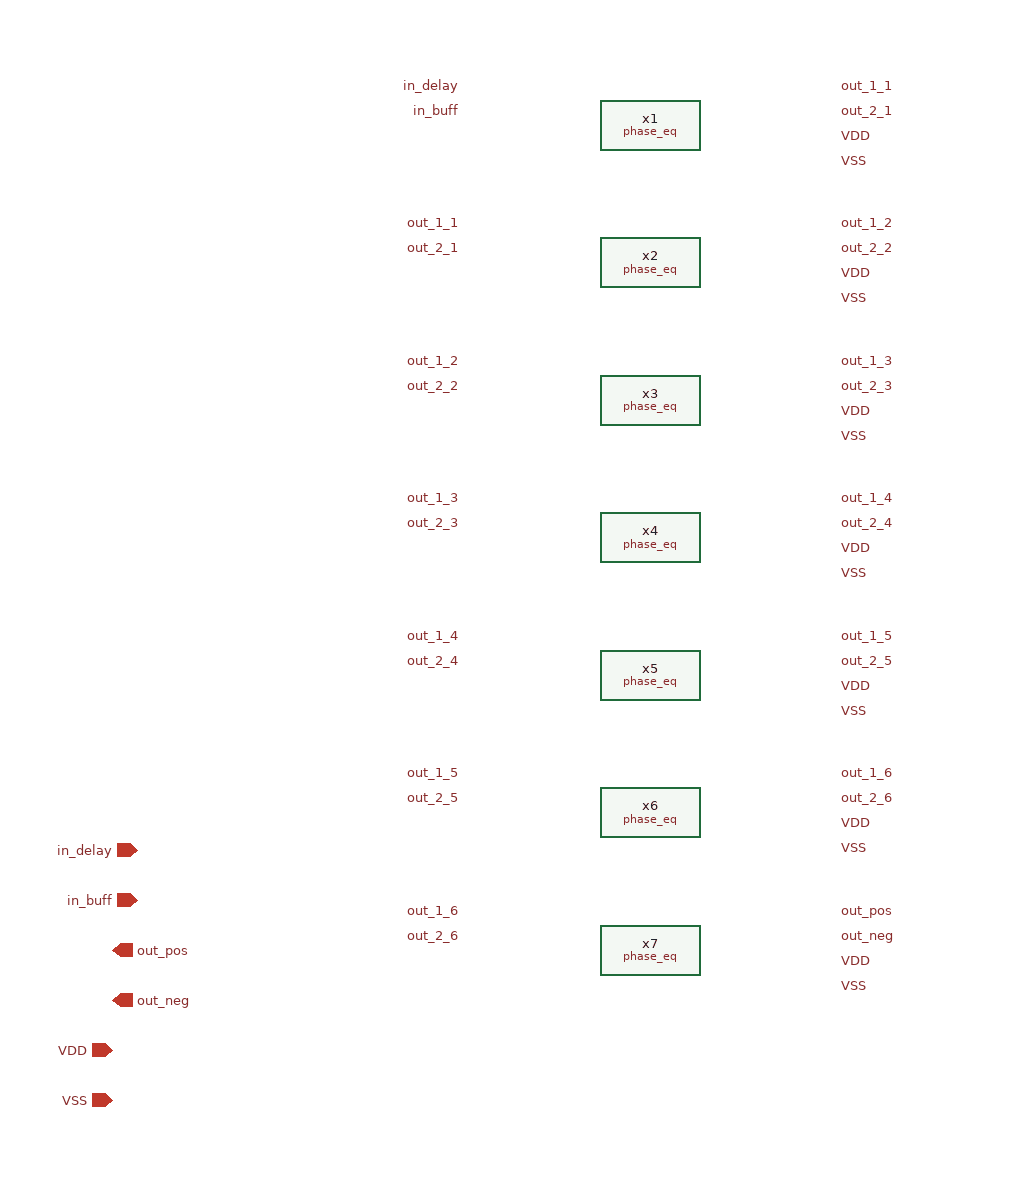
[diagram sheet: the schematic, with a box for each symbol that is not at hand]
v {xschem version=3.4.5 file_version=1.2
}
G {}
K {}
V {}
S {}
E {}
C {devices/iopin.sym} 120 -120 0 0 {name=p1 lab=VDD}
C {devices/iopin.sym} 120 -80 0 0 {name=p2 lab=VSS}
C {devices/lab_pin.sym} 700 -850 0 1 {name=p7 sig_type=std_logic lab=VDD}
C {devices/lab_pin.sym} 700 -830 0 1 {name=p3 sig_type=std_logic lab=VSS}
C {devices/lab_pin.sym} 700 -890 0 1 {name=p4 sig_type=std_logic lab=out_1_1}
C {devices/lab_pin.sym} 700 -870 0 1 {name=p5 sig_type=std_logic lab=out_2_1}
C {devices/lab_pin.sym} 400 -890 0 0 {name=p6 sig_type=std_logic lab=in_delay}
C {devices/lab_pin.sym} 400 -870 0 0 {name=p8 sig_type=std_logic lab=in_buff}
C {devices/lab_pin.sym} 700 -780 0 1 {name=p11 sig_type=std_logic lab=out_1_2}
C {devices/lab_pin.sym} 700 -760 0 1 {name=p12 sig_type=std_logic lab=out_2_2}
C {devices/lab_pin.sym} 400 -780 0 0 {name=p13 sig_type=std_logic lab=out_1_1}
C {devices/lab_pin.sym} 400 -760 0 0 {name=p14 sig_type=std_logic lab=out_2_1}
C {devices/lab_pin.sym} 700 -670 0 1 {name=p17 sig_type=std_logic lab=out_1_3}
C {devices/lab_pin.sym} 700 -650 0 1 {name=p18 sig_type=std_logic lab=out_2_3}
C {devices/lab_pin.sym} 400 -670 0 0 {name=p19 sig_type=std_logic lab=out_1_2}
C {devices/lab_pin.sym} 400 -650 0 0 {name=p20 sig_type=std_logic lab=out_2_2}
C {devices/lab_pin.sym} 700 -560 0 1 {name=p23 sig_type=std_logic lab=out_1_4}
C {devices/lab_pin.sym} 700 -540 0 1 {name=p24 sig_type=std_logic lab=out_2_4}
C {devices/lab_pin.sym} 400 -560 0 0 {name=p25 sig_type=std_logic lab=out_1_3}
C {devices/lab_pin.sym} 400 -540 0 0 {name=p26 sig_type=std_logic lab=out_2_3}
C {devices/lab_pin.sym} 700 -450 0 1 {name=p29 sig_type=std_logic lab=out_1_5}
C {devices/lab_pin.sym} 700 -430 0 1 {name=p30 sig_type=std_logic lab=out_2_5}
C {devices/lab_pin.sym} 400 -450 0 0 {name=p31 sig_type=std_logic lab=out_1_4}
C {devices/lab_pin.sym} 400 -430 0 0 {name=p32 sig_type=std_logic lab=out_2_4}
C {devices/lab_pin.sym} 700 -340 0 1 {name=p35 sig_type=std_logic lab=out_1_6}
C {devices/lab_pin.sym} 700 -320 0 1 {name=p36 sig_type=std_logic lab=out_2_6}
C {devices/lab_pin.sym} 400 -340 0 0 {name=p37 sig_type=std_logic lab=out_1_5}
C {devices/lab_pin.sym} 400 -320 0 0 {name=p38 sig_type=std_logic lab=out_2_5}
C {devices/lab_pin.sym} 700 -230 0 1 {name=p41 sig_type=std_logic lab=out_pos}
C {devices/lab_pin.sym} 700 -210 0 1 {name=p42 sig_type=std_logic lab=out_neg}
C {devices/lab_pin.sym} 400 -230 0 0 {name=p43 sig_type=std_logic lab=out_1_6}
C {devices/lab_pin.sym} 400 -210 0 0 {name=p44 sig_type=std_logic lab=out_2_6}
C {devices/ipin.sym} 140 -280 0 0 {name=p45 lab=in_delay}
C {devices/opin.sym} 120 -200 0 0 {name=p46 lab=out_pos}
C {devices/ipin.sym} 140 -240 0 0 {name=p47 lab=in_buff}
C {devices/opin.sym} 120 -160 0 0 {name=p48 lab=out_neg}
C {phase_eq.sym} 550 -860 0 0 {name=x1}
C {devices/lab_pin.sym} 700 -740 0 1 {name=p9 sig_type=std_logic lab=VDD}
C {devices/lab_pin.sym} 700 -720 0 1 {name=p10 sig_type=std_logic lab=VSS}
C {phase_eq.sym} 550 -750 0 0 {name=x2}
C {devices/lab_pin.sym} 700 -630 0 1 {name=p15 sig_type=std_logic lab=VDD}
C {devices/lab_pin.sym} 700 -610 0 1 {name=p16 sig_type=std_logic lab=VSS}
C {phase_eq.sym} 550 -640 0 0 {name=x3}
C {devices/lab_pin.sym} 700 -520 0 1 {name=p21 sig_type=std_logic lab=VDD}
C {devices/lab_pin.sym} 700 -500 0 1 {name=p22 sig_type=std_logic lab=VSS}
C {phase_eq.sym} 550 -530 0 0 {name=x4}
C {devices/lab_pin.sym} 700 -410 0 1 {name=p27 sig_type=std_logic lab=VDD}
C {devices/lab_pin.sym} 700 -390 0 1 {name=p28 sig_type=std_logic lab=VSS}
C {phase_eq.sym} 550 -420 0 0 {name=x5}
C {devices/lab_pin.sym} 700 -300 0 1 {name=p33 sig_type=std_logic lab=VDD}
C {devices/lab_pin.sym} 700 -280 0 1 {name=p34 sig_type=std_logic lab=VSS}
C {phase_eq.sym} 550 -310 0 0 {name=x6}
C {devices/lab_pin.sym} 700 -190 0 1 {name=p39 sig_type=std_logic lab=VDD}
C {devices/lab_pin.sym} 700 -170 0 1 {name=p40 sig_type=std_logic lab=VSS}
C {phase_eq.sym} 550 -200 0 0 {name=x7}
